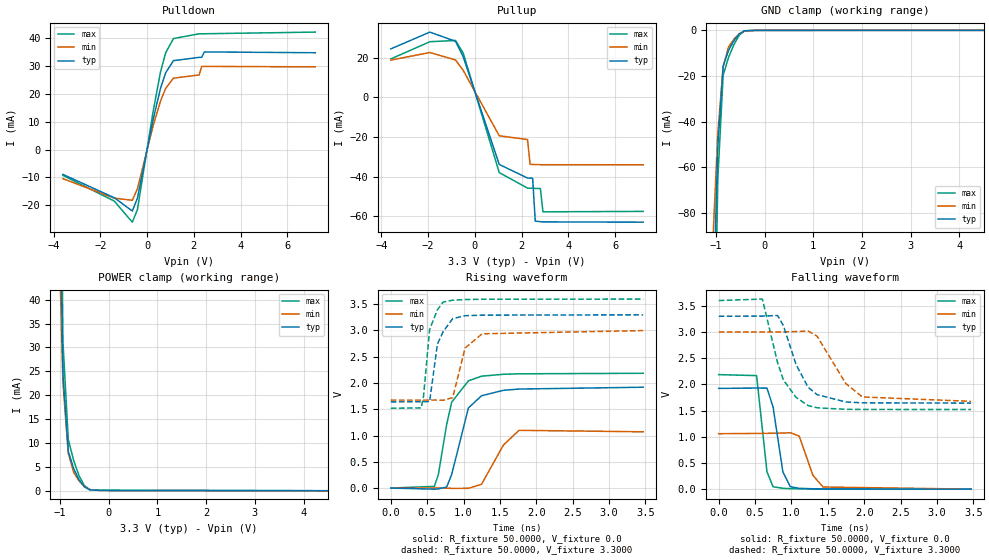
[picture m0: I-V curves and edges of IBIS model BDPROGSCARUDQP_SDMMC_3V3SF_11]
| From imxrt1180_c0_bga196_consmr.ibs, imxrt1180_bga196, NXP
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[Model]  BDPROGSCARUDQP_SDMMC_3V3SF_11
|   Model BDPROGSCARUDQP_SDMMC_3V3SF_11
| This model was characterised for following simulation conditions:
| External (pad) voltage:
|   - Typ: 3.3V,   - Min: 3.0V,   - Max: 3.6V
| Library cells for typ/min/max conditions are connected as defined below:
|  IO - External Pad
|  A - Core Input
|  EN - Output Buffer Enable
|  ASRCN3V3[0] - REFH3V3 gnde REFH3V3
|  ASRCN3V3[1] - REFH3V3 REFH3V3 gnde
|  ASRCN3V3[2] - gnde
|  ASRCN3V3[3] - gnde REFH3V3 gnde
|  ASRCP3V3[0] - vdde3v3 vdde3v3 REFL3V3
|  ASRCP3V3[1] - vdde3v3 REFL3V3 vdde3v3
|  ASRCP3V3[2] - REFL3V3 vdde3v3 vdde3v3
|  ASRCP3V3[3] - REFL3V3 REFL3V3 vdde3v3
|  IOGC - NC
|  PDRV - vdd
|  PSW - vdd
|  REFH3V3 - REFH3V3
|  REFL3V3 - REFL3V3
|  ZI - NC
|  gnd - gnd
|  gnde - gnde
|  vdd - vdd
|  vdde3v3 - vdde3v3
| All other pins connected to ground
Model_type I/O
Polarity   Non-Inverting
Enable   Active-Low
Vinl =   0.7500V
Vinh =   2.2500V
Vmeas =  1.6500V
Cref =   30.0000pF
Rref =   1.0000M
Vref =   3.3000V
C_comp   2.1236pF   2.1089pF   2.1446pF
|C_comp_pullup   0.3619pF   0.3752pF   0.3519pF
|C_comp_pulldown   0.6265pF   0.6593pF   0.5997pF
[Model Spec]
| variable   typ   min   max
Vinh   2.0625V   1.8750V   2.2500V
Vinl   0.8250V   0.7500V   0.9000V
[Temperature Range]   25.0000   0.1050k   -20.0000
[Voltage Range]   3.3000V   3.0000V   3.6000V
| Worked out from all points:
|   slope of the pulldown table from 0 to 0.495 V, typ, clamps not added: 25.5 ohm
|   slope of the pullup table from 0 to 0.495 V, typ, clamps not added: 26.4 ohm
|   GND clamp passes 1 mA (typ) near -0.48 V on its own axis
|   POWER clamp passes 1 mA (typ) near -0.51 V on its own axis
|   rising waveform, R_fixture 50.0000, V_fixture 0.0: 20-80 % time 215ps typ, 257ps min, 191ps max; typ from 0 V to 1.92 V
|   rising waveform, R_fixture 50.0000, V_fixture 3.3000: 20-80 % time 135ps typ, 161ps min, 120ps max; typ from 1.64 V to 3.3 V
|   falling waveform, R_fixture 50.0000, V_fixture 0.0: 20-80 % time 124ps typ, 162ps min, 93.1ps max; typ from 1.92 V to 0 V
|   falling waveform, R_fixture 50.0000, V_fixture 3.3000: 20-80 % time 290ps typ, 367ps min, 260ps max; typ from 3.3 V to 1.64 V
[Pulldown]
|Voltage   I(typ)   I(min)   I(max)
-3.6V     -8.96mA    -10.5mA    -9.321mA
-1.4V     -17.38mA   -17.54mA   -18.58mA
-630mV    -22.15mA   -18.28mA   -26.18mA
-410mV    -17.5mA    -14.09mA   -21.62mA
250mV     10.41mA    8.226mA    13.2mA
580mV     22.14mA    17.5mA     28.06mA
800mV     27.69mA    22.05mA    34.89mA
1.13V     32mA       25.7mA     39.96mA
2.23V     33.19mA    26.86mA    41.68mA
2.34V     33.2mA     29.91mA    41.68mA
2.45V     35.15mA    29.93mA    41.69mA
7.2V      34.85mA    29.77mA    42.29mA
[Pullup]
|Voltage   I(typ)   I(min)   I(max)
-3.6V     24.55mA    18.87mA    19.48mA
-1.93V    33.06mA    22.74mA    28.19mA
-830mV    28.38mA    18.94mA    28.82mA
-500mV    20.5mA     13.65mA    22.35mA
1.04V     -33.9mA    -19.39mA   -38mA
2.25V     -40.75mA   -21.29mA   -45.86mA
2.36V     -40.82mA   -33.82mA   -45.91mA
2.47V     -40.88mA   -33.89mA   -45.96mA
2.58V     -62.51mA   -33.95mA   -46mA
2.8V      -62.83mA   -34.01mA   -46.07mA
2.91V     -62.93mA   -34.02mA   -57.84mA
7.2V      -63.09mA   -34.06mA   -57.63mA
[GND_clamp]
|Voltage   I(typ)   I(min)   I(max)
-3.6V     -5.131A    -2.969A    -8.406A
-1.07V    -134.2mA   -96.54mA   -200.7mA
-960mV    -50.84mA   -45.29mA   -65.28mA
-850mV    -15.74mA   -15.96mA   -19.63mA
-740mV    -8.808mA   -7.274mA   -11.89mA
-630mV    -4.596mA   -3.904mA   -6.316mA
-520mV    -1.551mA   -1.569mA   -2.126mA
-410mV    -182.3uA   -313uA     -219.4uA
-190mV    -16.94uA   -13.41uA   -23.77uA
7.2V      0A         0A         0A
[POWER_clamp]
|Voltage   I(typ)   I(min)   I(max)
-3.6V     5.01A      2.85A      8.324A
-1.05V    90.64mA    63.89mA    144.9mA
-940mV    24.29mA    22.59mA    31.15mA
-830mV    8.246mA    7.833mA    10.76mA
-720mV    4.663mA    3.912mA    6.37mA
-610mV    2.344mA    2.102mA    3.186mA
-500mV    850.8uA    907.7uA    1.111mA
-390mV    222uA      289.9uA    270.2uA
-170mV    103uA      76.12uA    142.4uA
7.2V      0A         0A         0A
[Ramp]
| variable   typ   min   max
dV/dt_r  1.1521/0.2146n   0.6423/0.2565n   1.3109/0.1906n
dV/dt_f  0.9946/0.2895n   0.7941/0.3667n   1.2466/0.2597n
R_load = 50.0000
[Rising Waveform]
R_fixture= 50.0000
V_fixture= 0.0
V_fixture_min= 0.0
V_fixture_max= 0.0
|time   V(typ)   V(min)   V(max)
0s        169.4uV    143uV      212.9uV
598.6ps   -21.02mV   209.2uV    32.03mV
654.5ps   -15.23mV   120uV      262.2mV
767.9ps   20.2mV     -2.045mV   1.21V
836.5ps   256.6mV    -6.103mV   1.635V
1.067ns   1.525V     -4.851mV   2.041V
1.247ns   1.757V     71.83mV    2.13V
1.549ns   1.861V     820.5mV    2.166V
1.762ns   1.885V     1.099V     2.175V
3.47ns    1.92V      1.071V     2.185V
[Rising Waveform]
R_fixture= 50.0000
V_fixture= 3.3000
V_fixture_min= 3.0000
V_fixture_max= 3.6000
|time   V(typ)   V(min)   V(max)
0s        1.641V     1.674V     1.52V
417.9ps   1.643V     1.674V     1.526V
449.7ps   1.643V     1.674V     1.744V
533.6ps   1.647V     1.674V     3.019V
640.1ps   2.737V     1.675V     3.392V
717.4ps   2.972V     1.671V     3.539V
850.2ps   3.225V     1.72V      3.577V
1.021ns   3.281V     2.666V     3.589V
1.256ns   3.292V     2.937V     3.594V
3.47ns    3.298V     2.998V     3.598V
[Falling Waveform]
R_fixture= 50.0000
V_fixture= 0.0
V_fixture_min= 0.0
V_fixture_max= 0.0
|time   V(typ)   V(min)   V(max)
0s        1.922V     1.058V     2.185V
520.5ps   1.929V     1.063V     2.166V
663.1ps   1.927V     1.065V     331.1mV
747.1ps   1.568V     1.066V     46.67mV
881.9ps   329.9mV    1.071V     16.18mV
984.6ps   46.48mV    1.076V     10.18mV
1.106ns   16.58mV    1.014V     6.563mV
1.295ns   7.766mV    264mV      3.61mV
1.434ns   5.253mV    41.13mV    2.422mV
3.47ns    189.6uV    332.4uV    215.9uV
[Falling Waveform]
R_fixture= 50.0000
V_fixture= 3.3000
V_fixture_min= 3.0000
V_fixture_max= 3.6000
|time   V(typ)   V(min)   V(max)
0s        3.298V     2.998V     3.598V
599.7ps   3.301V     2.998V     3.626V
809.3ps   3.312V     3V         2.412V
889.7ps   3.118V     3V         2.081V
1.062ns   2.38V      3.007V     1.752V
1.228ns   1.945V     3.016V     1.596V
1.351ns   1.804V     2.92V      1.552V
1.747ns   1.663V     2.015V     1.523V
1.974ns   1.647V     1.759V     1.521V
3.47ns    1.641V     1.675V     1.52V
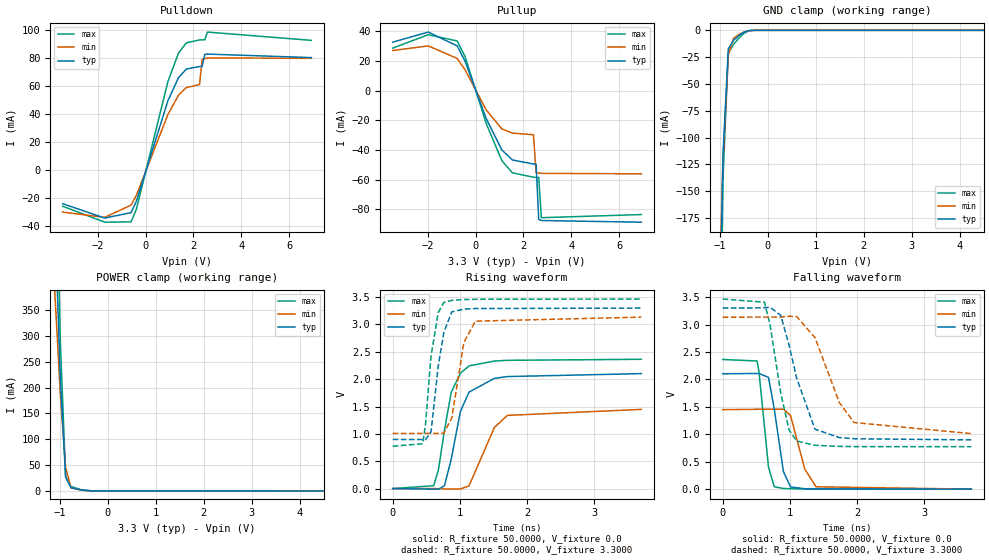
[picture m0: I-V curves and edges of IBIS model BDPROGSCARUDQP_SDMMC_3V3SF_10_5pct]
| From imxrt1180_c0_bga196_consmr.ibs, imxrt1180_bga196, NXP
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[Model]  BDPROGSCARUDQP_SDMMC_3V3SF_10_5pct
|   Model BDPROGSCARUDQP_SDMMC_3V3SF_10_5pct
| This model was characterised for following simulation conditions:
| External (pad) voltage:
|   - Typ: 3.3V,   - Min: 3.135V,   - Max: 3.465V
| Library cells for typ/min/max conditions are connected as defined below:
|  IO - External Pad
|  A - Core Input
|  EN - Output Buffer Enable
|  ASRCN3V3[0] - REFH3V3
|  ASRCN3V3[1] - REFH3V3 REFH3V3 gnde
|  ASRCN3V3[2] - gnde
|  ASRCN3V3[3] - gnde REFH3V3 gnde
|  ASRCP3V3[0] - vdde3v3 REFL3V3 REFL3V3
|  ASRCP3V3[1] - vdde3v3 REFL3V3 vdde3v3
|  ASRCP3V3[2] - REFL3V3 vdde3v3 vdde3v3
|  ASRCP3V3[3] - REFL3V3 REFL3V3 vdde3v3
|  IOGC - NC
|  PDN - vdd
|  PDRV - gnd
|  PSW - vdd
|  PUN - vdd
|  REFH3V3 - REFH3V3
|  REFL3V3 - REFL3V3
|  ZI - NC
|  gnd - gnd
|  gnde - gnde
|  vdd - vdd
|  vdde3v3 - vdde3v3
| All other pins connected to ground
Model_type I/O
Polarity   Non-Inverting
Enable   Active-Low
Vinl =   0.7500V
Vinh =   2.2500V
Vmeas =  1.6500V
Cref =   30.0000pF
Rref =   1.0000M
Vref =   3.3000V
C_comp   2.0930pF   2.0578pF   2.1401pF
|C_comp_pullup   0.3784pF   0.3909pF   0.3685pF
|C_comp_pulldown   0.6261pF   0.6567pF   0.6006pF
[Model Spec]
| variable   typ   min   max
Vinh   2.0625V   1.9594V   2.1656V
Vinl   0.8250V   0.7837V   0.8662V
[Temperature Range]   25.0000   0.1050k   -20.0000
[Voltage Range]   3.3000V   3.1350V   3.4650V
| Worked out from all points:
|   slope of the pulldown table from 0 to 0.495 V, typ, clamps not added: 17.8 ohm
|   slope of the pullup table from 0 to 0.495 V, typ, clamps not added: 23.8 ohm
|   GND clamp passes 1 mA (typ) near -0.44 V on its own axis
|   POWER clamp passes 1 mA (typ) near -0.50 V on its own axis
|   rising waveform, R_fixture 50.0000, V_fixture 0.0: 20-80 % time 239ps typ, 291ps min, 208ps max; typ from 0 V to 2.1 V
|   rising waveform, R_fixture 50.0000, V_fixture 3.3000: 20-80 % time 145ps typ, 167ps min, 137ps max; typ from 0.899 V to 3.3 V
|   falling waveform, R_fixture 50.0000, V_fixture 0.0: 20-80 % time 145ps typ, 188ps min, 115ps max; typ from 2.1 V to 0 V
|   falling waveform, R_fixture 50.0000, V_fixture 3.3000: 20-80 % time 298ps typ, 403ps min, 221ps max; typ from 3.3 V to 0.898 V
[Pulldown]
|Voltage   I(typ)   I(min)   I(max)
-3.465V   -23.98mA   -29.97mA   -25.8mA
-1.705V   -34.25mA   -33.72mA   -37.18mA
-605mV    -30.33mA   -24.95mA   -36.92mA
-385mV    -22.24mA   -17.93mA   -27.96mA
935mV     49.66mA    39.81mA    63.36mA
1.375V    66.01mA    53.5mA     83.56mA
1.705V    72.25mA    59.04mA    90.99mA
2.255V    74.04mA    61.13mA    93.06mA
2.365V    74.11mA    79.12mA    93.11mA
2.475V    82.72mA    79.73mA    93.16mA
2.585V    82.93mA    80.21mA    98.65mA
6.93V     80.43mA    79.9mA     92.74mA
[Pullup]
|Voltage   I(typ)   I(min)   I(max)
-3.465V   32.75mA    27.12mA    28.75mA
-1.98V    39.56mA    30.24mA    37.78mA
-770mV    30.26mA    21.79mA    33.57mA
-440mV    19.92mA    14.2mA     23.06mA
440mV     -18.65mA   -12.89mA   -21.91mA
1.1V      -40.01mA   -25.8mA    -47.26mA
1.54V     -46.72mA   -28.62mA   -55.4mA
2.42V     -49.48mA   -29.7mA    -58.4mA
2.53V     -49.59mA   -55.15mA   -58.51mA
2.64V     -86.82mA   -55.51mA   -58.6mA
2.75V     -87.61mA   -55.78mA   -85.7mA
6.93V     -88.73mA   -56.08mA   -83.57mA
[GND_clamp]
|Voltage   I(typ)   I(min)   I(max)
-3.465V   -6.61A     -3.74A     -10.67A
-1.045V   -379.3mA   -292.6mA   -527.3mA
-935mV    -115.6mA   -121.5mA   -138.8mA
-825mV    -17.39mA   -23.01mA   -21.23mA
-715mV    -9.283mA   -7.4mA     -13.11mA
-605mV    -4.963mA   -3.854mA   -7.31mA
-495mV    -1.742mA   -1.524mA   -2.691mA
-385mV    -190.8uA   -276.7uA   -290.1uA
-275mV    -4.391uA   -16.17uA   -3.827uA
6.93V     0A         0A         0A
[POWER_clamp]
|Voltage   I(typ)   I(min)   I(max)
-3.465V   6.781A     3.823A     11A
-1.1V     518.6mA    375.5mA    743.7mA
-990mV    215.3mA    186.8mA    288.2mA
-880mV    27.02mA    45.34mA    26.73mA
-770mV    6.184mA    6.16mA     8.549mA
-550mV    1.523mA    1.344mA    2.266mA
-330mV    50.46uA    94.19uA    71.53uA
6.93V     0A         0A         0A
[Ramp]
| variable   typ   min   max
dV/dt_r  1.2610/0.2391n   0.8690/0.2911n   1.4184/0.2076n
dV/dt_f  1.4409/0.2978n   1.2730/0.4034n   1.6145/0.2214n
R_load = 50.0000
[Rising Waveform]
R_fixture= 50.0000
V_fixture= 0.0
V_fixture_min= 0.0
V_fixture_max= 0.0
|time   V(typ)   V(min)   V(max)
0s        27nV       298.3nV    61.58nV
609.8ps   -10.39mV   -232.5uV   52.61mV
680.9ps   -10.65mV   -2.053mV   346.1mV
771.3ps   53.33mV    -5.264mV   1.076V
871.4ps   539.5mV    -8.567mV   1.762V
1.007ns   1.409V     -8.543mV   2.108V
1.136ns   1.764V     50.28mV    2.243V
1.514ns   2.016V     1.12V      2.332V
1.707ns   2.048V     1.338V     2.345V
3.7ns     2.102V     1.448V     2.364V
[Rising Waveform]
R_fixture= 50.0000
V_fixture= 3.3000
V_fixture_min= 3.1350
V_fixture_max= 3.4650
|time   V(typ)   V(min)   V(max)
0s        899mV      1.01V      774.6mV
446.5ps   896.3mV    1.01V      820mV
487.9ps   892.9mV    1.01V      1.168V
570ps     1.034V     1.01V      2.421V
677.2ps   2.238V     1.007V     3.217V
760.8ps   2.854V     1.012V     3.405V
879.3ps   3.231V     1.292V     3.441V
1.059ns   3.281V     2.671V     3.456V
1.231ns   3.292V     3.061V     3.461V
3.7ns     3.3V       3.135V     3.465V
[Falling Waveform]
R_fixture= 50.0000
V_fixture= 0.0
V_fixture_min= 0.0
V_fixture_max= 0.0
|time   V(typ)   V(min)   V(max)
0s        2.103V     1.449V     2.364V
511.5ps   2.109V     1.456V     2.336V
539.6ps   2.109V     1.457V     2.138V
682.1ps   2.037V     1.458V     397.1mV
767.7ps   1.46V      1.457V     43.49mV
903.5ps   321.2mV    1.457V     12.96mV
1.009ns   40.3mV     1.344V     7.8mV
1.221ns   8.566mV    366.8mV    3.737mV
1.389ns   4.949mV    43.27mV    2.241mV
3.7ns     78.91uV    173.3uV    44.78uV
[Falling Waveform]
R_fixture= 50.0000
V_fixture= 3.3000
V_fixture_min= 3.1350
V_fixture_max= 3.4650
|time   V(typ)   V(min)   V(max)
0s        3.3V       3.135V     3.465V
621.3ps   3.305V     3.136V     3.408V
702.3ps   3.318V     3.136V     3.013V
863.4ps   3.169V     3.137V     1.753V
987.2ps   2.627V     3.152V     1.08V
1.1ns     2.027V     3.147V     878.2mV
1.373ns   1.093V     2.764V     799.9mV
1.737ns   940mV      1.576V     779.8mV
1.957ns   918.9mV    1.214V     776.2mV
3.7ns     898.4mV    1.013V     774.1mV
